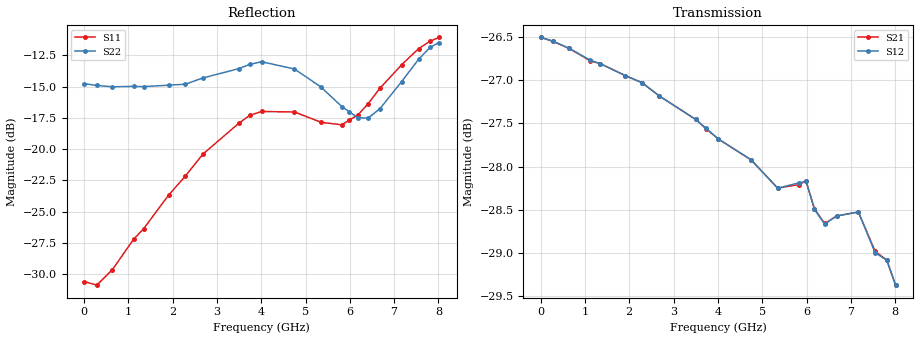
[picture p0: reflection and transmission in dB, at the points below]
! DEVICE ID: PE43712
! File Path: z:\PE43713\PE43713_CHAR_NOM_04292014\AMB\3p300\LS_ATT_25p25dB\PE43713_AMB_3p300V_3p000V_0p000V_LS_ATT_25p25dB_S2P_SN_10_A0139A.s2p
! Serial: 10
! Lot: A0139A
! Temp: 25C
! VDD: 3.300
! VSS: 0.000
! Control_Hi: 3.000
! Control_Lo: 0.000
! Attenuation Step: 25.25dB
! Port 1: RF1
! Port 2: RF2
! ThroughPath:1-2
! IDD: 0.0001453912
! ISS: -7.22e-008
#  Hz  S  RI  R  50
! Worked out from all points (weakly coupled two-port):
!   801 points, 10 MHz to 8.01 GHz, reference 50 ohm
!   highest |S21| = -26.50 dB at 10 MHz (marker M1); lowest = -29.4 dB at 8.01 GHz (marker M2)
!   lowest |S11| = -30.9 dB at 290 MHz (marker M3), VSWR 1.06, Z = 47.4 + j1.03 ohm
!   |S11| at or under -10 dB: start of sweep to end of sweep
!   |S22| runs from -17.6 to -11.5 dB; largest |S21 - S12| = 0.00017
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1e7  -0.0295 0.000792  0.0473 -0.000232  0.0473 -0.00022  -0.1828 0.00126
2.9e8  -0.0264 0.0109  0.0468 -0.00479  0.0468 -0.0048  -0.1787 0.0199
6.4e8  -0.0234 0.0231  0.0455 -0.0101  0.0455 -0.0102  -0.1725 0.0421
1.12e9  -0.0179 0.0397  0.0427 -0.0167  0.0427 -0.0168  -0.1631 0.072
1.35e9  -0.0133 0.0462  0.0412 -0.0197  0.0412 -0.0197  -0.1565 0.0844
1.91e9  0.000793 0.0654  0.0366 -0.0261  0.0366 -0.0261  -0.1354 0.1189
2.29e9  0.0133 0.0769  0.0329 -0.03  0.0329 -0.03  -0.1183 0.1381
2.68e9  0.0267 0.0915  0.0286 -0.0331  0.0286 -0.0331  -0.0986 0.1653
3.5e9  0.0457 0.1186  0.0188 -0.038  0.0188 -0.038  -0.069 0.1984
3.74e9  0.0495 0.1271  0.0157 -0.0388  0.0158 -0.0388  -0.0647 0.2084
4.01e9  0.0533 0.131  0.0124 -0.0394  0.0124 -0.0394  -0.0615 0.215
4.75e9  0.0636 0.1256  0.00371 -0.04  0.00375 -0.04  -0.0409 0.2052
5.35e9  0.0802 0.0998  -0.00253 -0.0386  -0.00252 -0.0386  -0.0212 0.1758
5.82e9  0.1012 0.0735  -0.00769 -0.0381  -0.00762 -0.0382  0.0145 0.1472
5.99e9  0.1129 0.0658  -0.0102 -0.0377  -0.0101 -0.0377  0.0313 0.1375
6.18e9  0.1248 0.0562  -0.0122 -0.0356  -0.0121 -0.0356  0.052 0.123
6.41e9  0.1433 0.0497  -0.0131 -0.0345  -0.013 -0.0345  0.079 0.107
6.68e9  0.1698 0.0437  -0.0155 -0.0339  -0.0155 -0.0339  0.1118 0.0926
7.17e9  0.2139 0.0399  -0.0212 -0.0309  -0.0212 -0.0309  0.166 0.0847
7.55e9  0.2484 0.0433  -0.0237 -0.0265  -0.0236 -0.0265  0.2109 0.0884
7.81e9  0.2659 0.0481  -0.0251 -0.0246  -0.0251 -0.0246  0.2373 0.094
8.01e9  0.275 0.0522  -0.0253 -0.0227  -0.0253 -0.0227  0.2496 0.0944
